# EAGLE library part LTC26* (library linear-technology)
Dual 16-/14-/12-Bit Rail-to-Rail DACs Source: www.linear.com

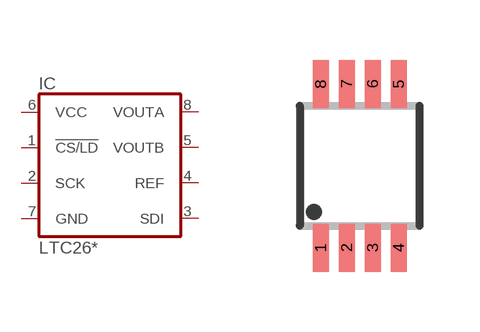
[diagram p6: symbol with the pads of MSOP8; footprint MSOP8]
Designator prefix IC

## LTC2602CMS8 (MPN: LTC2602CMS8; OC_FARNELL: 1330944; OC_NEWARK: 56M5818), LTC2602IMS8 (MPN: LTC2602IMS8; OC_FARNELL: 1663694; OC_NEWARK: 56M5822), LTC2612CMS8 (MPN: LTC2612CMS8; OC_FARNELL: 1330947; OC_NEWARK: 56M5926), LTC2612IMS8 (MPN: LTC2612IMS8; OC_FARNELL: unknown; OC_NEWARK: 56M5930), LTC2622CMS8 (MPN: LTC2622CMS8; OC_FARNELL: 1330954; OC_NEWARK: 56M6034), LTC2622IMS8 (MPN: LTC2622IMS8; OC_FARNELL: unknown; OC_NEWARK: 56M6038)  [MSOP8]
1  !CS/LD  in
2  SCK  in
3  SDI  in
4  REF  in
5  VOUTB  out
6  VCC  pwr
7  GND  pwr
8  VOUTA  out

## Footprint MSOP8 (pad centres in mm)
MSOP8
smd 0.4 x 1.2: 1 -0.975,-2.05; 2 -0.325,-2.05; 3 0.325,-2.05; 4 0.975,-2.05; 5 0.975,2.05; 6 0.325,2.05; 7 -0.325,2.05; 8 -0.975,2.05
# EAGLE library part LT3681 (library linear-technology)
36V, 2A, 2.8MHz Step-Down Switching Regulator with Integrated Power Schottky Diode Source: http://www.linear.com/pc/downloadDocument.do?navId=H0,C1,C1003,C1042,C1032,C1064,P38040,D25144

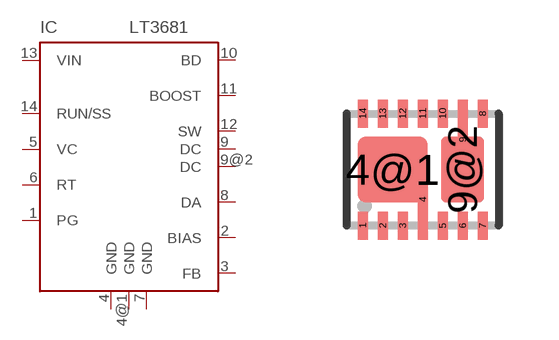
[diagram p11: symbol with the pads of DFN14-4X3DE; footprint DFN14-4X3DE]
Designator prefix IC

## LT3681 (MPN: LT3681EDE#PBF; OC_FARNELL: 1627603; OC_NEWARK: 57M8550)  [DFN14-4X3DE]
1  PG  oc
2  BIAS  in
3  FB  in
4  GND  in
4@1  GND  in
5  VC  out
6  RT  in
7  GND  in
8  DA  pas
9  DC  pas
9@2  DC  pas
10  BD  in
11  BOOST  out
12  SW  out
13  VIN  in
14  RUN/SS  in

## Footprint DFN14-4X3DE (pad centres in mm)
14-LEAD (4mm x 2mm) PALSTIC DFN DE14MA PACKAGE Source: http://www.linear.com/pc/downloadDocument.do?navId=H0,C1,C1003,C1042,C1032,C1064,P38040,D25144
smd 0.25 x 0.7: 1 -1.5,-1.4; 2 -1,-1.4; 3 -0.5,-1.4; 5 0.5,-1.4; 6 1,-1.4; 7 1.5,-1.4; 8 1.5,1.4; 10 0.5,1.4; 11 0,1.4; 12 -0.5,1.4; 13 -1,1.4; 14 -1.5,1.4
smd 0.25 x 2: 4 0,-0.75; 9 1,0.75
smd 1.75 x 1.65: 4@1 -0.75,0
smd 1.07 x 1.65: 9@2 1,0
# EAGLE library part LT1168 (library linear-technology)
Low Power, Single Resistor Gain Programmable, Precision Instrumentation Amplifier SourcE: LT1168.pdf

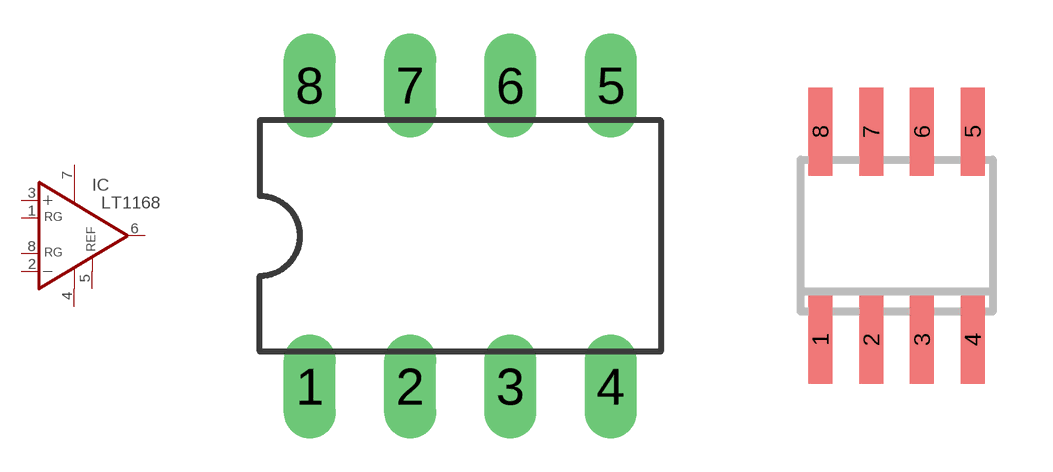
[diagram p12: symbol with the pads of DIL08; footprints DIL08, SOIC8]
Designator prefix IC

## LT1168ACN8 (OC_FARNELL: unknown; OC_NEWARK: unknown), LT1168AIN8 (OC_FARNELL: unknown; OC_NEWARK: unknown), LT1168CN8 (MPN: LT1168CN8#PBF; OC_FARNELL: 1330587; OC_NEWARK: 57M2327), LT1168IN8 (MPN: LT1168IN8; OC_FARNELL: unknown; OC_NEWARK: 57M2332)  [DIL08]
1  RG  in
2  -IN  in
3  +IN  in
4  V-  pwr
5  REF  in
6  OUT  out
7  V+  pwr
8  RG  in

## LT1168ACS8 (MPN: LT1168ACS8; OC_FARNELL: unknown; OC_NEWARK: 57M2316), LT1168AIS8 (MPN: LT1168AIS8; OC_FARNELL: unknown; OC_NEWARK: 57M2322), LT1168CS8 (MPN: LT1168CS8; OC_FARNELL: unknown; OC_NEWARK: 57M2328), LT1168IS8 (MPN: LT1168IS8; OC_FARNELL: unknown; OC_NEWARK: 57M2334)  [SOIC8]
Pads as for DIL08

## Footprint DIL08 (pad centres in mm)
Dual In Line Package
drill 0.813 long: 1 -3.81,-3.81; 2 -1.27,-3.81; 3 1.27,-3.81; 4 3.81,-3.81; 5 3.81,3.81; 6 1.27,3.81; 7 -1.27,3.81; 8 -3.81,3.81

## Footprint SOIC8 (pad centres in mm)
Small Outline IC
smd 0.6 x 2.2: 1 -1.905,-2.6; 2 -0.635,-2.6; 3 0.635,-2.6; 4 1.905,-2.6; 5 1.905,2.6; 6 0.635,2.6; 7 -0.635,2.6; 8 -1.905,2.6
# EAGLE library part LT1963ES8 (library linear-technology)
1.5A, Low Noise, Fast Transient Response LDO Regulator Source: http://www.linear.com/pc/downloadDocument.do?navId=H0,C3,P2222,D3148

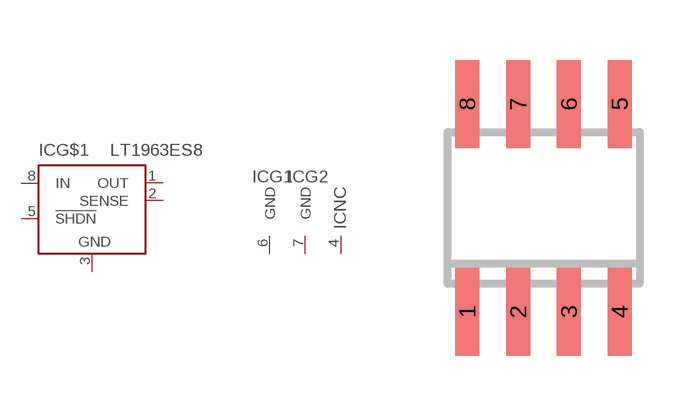
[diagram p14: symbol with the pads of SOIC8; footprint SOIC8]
Designator prefix IC; gates G$1=LT1129 G1=GND G2=GND NC=NC

## LT1963ES8 (MPN: LT1963ES8; OC_FARNELL: unknown; OC_NEWARK: 57M7550), LT1963ES8-1.5 (MPN: LT1963ES8-1.5; OC_FARNELL: unknown; OC_NEWARK: 57M7551), LT1963ES8-1.8 (MPN: LT1963ES8-1.8; OC_FARNELL: unknown; OC_NEWARK: 57M7555), LT1963ES8-2.5 (MPN: LT1963ES8-2.5; OC_FARNELL: unknown; OC_NEWARK: 57M7559), LT1963ES8-3.3 (MPN: LT1963ES8-3.3; OC_FARNELL: unknown; OC_NEWARK: 57M7563)  [SOIC8]
1  G$1:OUT  out
2  G$1:SENSE  in
3  G$1:GND  pwr
4  NC:NC  nc
5  G$1:!SHDN  in
6  G1:GND  pwr
7  G2:GND  pwr
8  G$1:IN  in

## Footprint SOIC8 (pad centres in mm)
Small Outline IC
smd 0.6 x 2.2: 1 -1.905,-2.6; 2 -0.635,-2.6; 3 0.635,-2.6; 4 1.905,-2.6; 5 1.905,2.6; 6 0.635,2.6; 7 -0.635,2.6; 8 -1.905,2.6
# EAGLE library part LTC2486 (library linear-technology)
16-Bit 2-/4-Channel Delta Sigma ADC with PGA and Easy Drive Input Current Cancellation Source: http://www.linear.com/pc/downloadDocument.do?navId=H0,C1,C1155,C1001,C1152,P36532,D19318

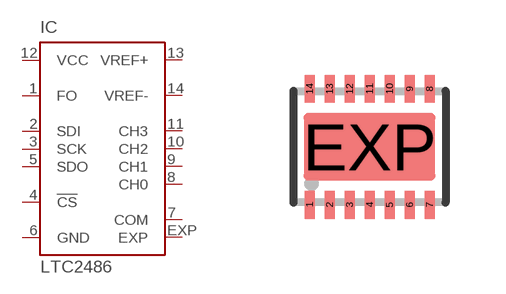
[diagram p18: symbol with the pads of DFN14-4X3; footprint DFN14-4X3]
Designator prefix IC

## LTC2486C (OC_FARNELL: unknown; OC_NEWARK: unknown), LTC2486I (OC_FARNELL: unknown; OC_NEWARK: unknown)  [DFN14-4X3]
1  FO  in
2  SDI  in
3  SCK  in
4  !CS  in
5  SDO  out
6  GND  pwr
7  COM  pwr
8  CH0  in
9  CH1  in
10  CH2  in
11  CH3  in
12  VCC  pwr
13  VREF+  in
14  VREF-  in
EXP  EXP  in

## Footprint DFN14-4X3 (pad centres in mm)
14-Lead Plastic DFN (4mm × 3mm) (Reference LTC DWG # 05-08-1708 Rev B) Source: http://www.linear.com/pc/downloadDocument.do?navId=H0,C1,C1155,C1001,C1152,P36532,D19318
smd 0.25 x 0.7: 1 -1.5,-1.45; 2 -1,-1.45; 3 -0.5,-1.45; 4 0,-1.45; 5 0.5,-1.45; 6 1,-1.45; 7 1.5,-1.45; 8 1.5,1.45; 9 1,1.45; 10 0.5,1.45; 11 0,1.45; 12 -0.5,1.45; 13 -1,1.45; 14 -1.5,1.45
smd 3.3 x 1.7: EXP 0,0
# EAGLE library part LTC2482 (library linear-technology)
16-Bit Delta Sigma ADC with Easy Drive Input Current Cancellation Source: http://www.linear.com/pc/downloadDocument.do?navId=H0,C1,C1155,C1001,C1152,P11253,D7998

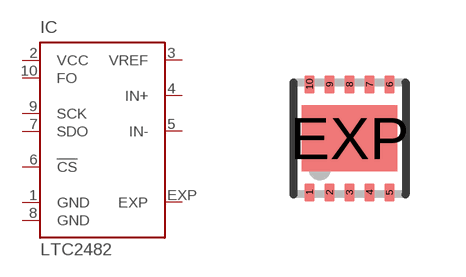
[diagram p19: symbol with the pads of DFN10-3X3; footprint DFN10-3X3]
Designator prefix IC

## LTC2482 (OC_FARNELL: 1330940; OC_NEWARK: unknown)  [DFN10-3X3]
1  GND  pwr
2  VCC  pwr
3  VREF  in
4  IN+  in
5  IN-  in
6  !CS  in
7  SDO  out
8  GND  pwr
9  SCK  in
10  FO  in
EXP  EXP  in

## Footprint DFN10-3X3 (pad centres in mm)
DD Package 10-Lead Plastic DFN (3mm × 3mm) (Reference LTC DWG # 05-08-1669) Source: http://www.linear.com .. 4062fa.pdf
smd 0.25 x 0.45: 1 -1,-1.35; 2 -0.5,-1.35; 3 0,-1.35; 4 0.5,-1.35; 5 1,-1.35; 6 1,1.35; 7 0.5,1.35; 8 0,1.35; 9 -0.5,1.35; 10 -1,1.35
smd 2.38 x 1.65: EXP 0,0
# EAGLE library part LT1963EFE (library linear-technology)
1.5A, Low Noise, Fast Transient Response LDO Regulator Source: http://cds.linear.com/docs/Datasheet/1963fc.pdf

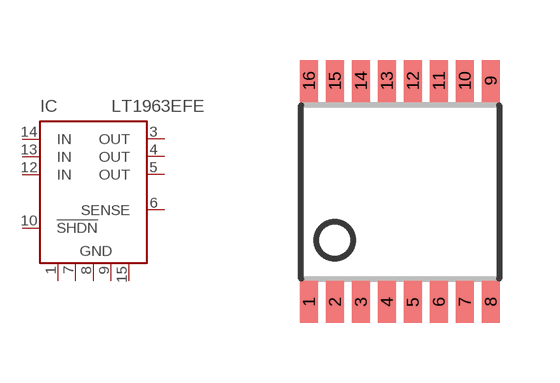
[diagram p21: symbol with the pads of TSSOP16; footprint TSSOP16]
Designator prefix IC

## LT1963EFE (MPN: LT1963EFE; OC_FARNELL: unknown; OC_NEWARK: 57M7494), LT1963EFE-1.5 (MPN: LT1963EFE-1.5; OC_FARNELL: unknown; OC_NEWARK: 57M7495), LT1963EFE-1.8 (MPN: LT1963EFE-1.8; OC_FARNELL: unknown; OC_NEWARK: 57M7499), LT1963EFE-2.5 (MPN: LT1963EFE-2.5; OC_FARNELL: unknown; OC_NEWARK: 57M7503), LT1963EFE-3.3 (MPN: LT1963EFE-3.3; OC_FARNELL: unknown; OC_NEWARK: 57M7507)  [TSSOP16]
1  GND  pwr
3  OUT  out
4  OUT  out
5  OUT  out
6  SENSE  in
7  GND  pwr
8  GND  pwr
9  GND  pwr
10  !SHDN  in
12  IN  in
13  IN  in
14  IN  in
15  GND  pwr

## Footprint TSSOP16 (pad centres in mm)
16-Lead Plastic TSSOP (4.4mm) http://cds.linear.com/docs/Datasheet/1963fc.pdf
smd 0.45 x 1.05: 1 -2.275,-2.768; 2 -1.625,-2.768; 3 -0.975,-2.768; 4 -0.325,-2.768; 5 0.325,-2.768; 6 0.975,-2.768; 7 1.625,-2.768; 8 2.275,-2.768; 9 2.275,2.768; 10 1.625,2.768; 11 0.975,2.768; 12 0.325,2.768; 13 -0.325,2.768; 14 -0.975,2.768; 15 -1.625,2.768; 16 -2.275,2.768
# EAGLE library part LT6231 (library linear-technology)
215MHz, Rail-to-Rail Output, 1.1nV/Hz, 3.5mA Op Amp Source: http://cds.linear.com/docs/Datasheet/623012fb.pdf

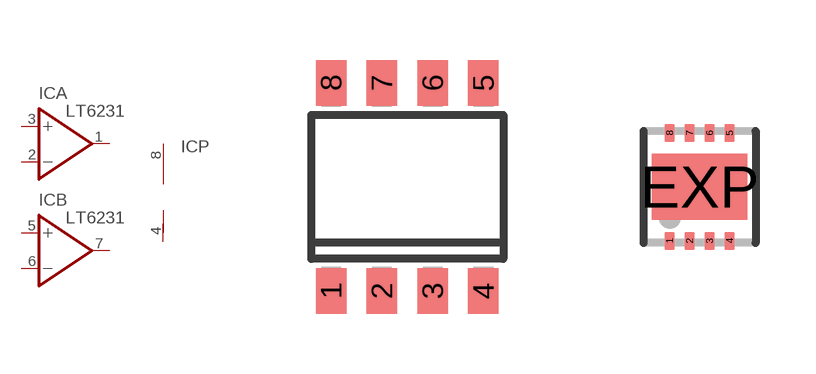
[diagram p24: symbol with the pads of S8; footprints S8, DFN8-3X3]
Designator prefix IC; gates A=OPAMP B=OPAMP P=V+-

## LT6231CS8 (MPN: LT6231CS8; OC_FARNELL: 1330763; OC_NEWARK: 57M9348), LT6231IS8 (MPN: LT6231IS8; OC_FARNELL: unknown; OC_NEWARK: 57M9356)  [S8]
1  A:OUT  out
2  A:-IN  in
3  A:+IN  in
4  P:V-  pwr
5  B:+IN  in
6  B:-IN  in
7  B:OUT  out
8  P:V+  pwr

## LT6231CDD (MPN: LT6231CDD; OC_FARNELL: unknown; OC_NEWARK: 57M9344), LT6231IDD (MPN: LT6231IDD; OC_FARNELL: unknown; OC_NEWARK: 57M9352)  [DFN8-3X3]
Pads as for S8

## Footprint S8 (pad centres in mm)
8-Lead Plastic Small Outline Narrow .150 Inch Source: http://cds.linear.com/docs/Datasheet/623012fb.pdf
smd 0.762 x 1.143: 1 -1.905,-2.6; 2 -0.635,-2.6; 3 0.635,-2.6; 4 1.905,-2.6; 5 1.905,2.6; 6 0.635,2.6; 7 -0.635,2.6; 8 -1.905,2.6

## Footprint DFN8-3X3 (pad centres in mm)
DD Package 8-Lead Plastic DFN (3mm × 3mm) Source: http://cds.linear.com/docs/Datasheet/623012fb.pdf
smd 0.25 x 0.45: 1 -0.75,-1.35; 2 -0.25,-1.35; 3 0.25,-1.35; 4 0.75,-1.35; 5 0.75,1.35; 6 0.25,1.35; 7 -0.25,1.35; 8 -0.75,1.35
smd 2.38 x 1.65: EXP 0,0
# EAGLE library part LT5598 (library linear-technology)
5MHz to 1600MHz High Linearity Direct Quadrature Modulator Source: http://cds.linear.com/docs/Datasheet/5598f.pdf

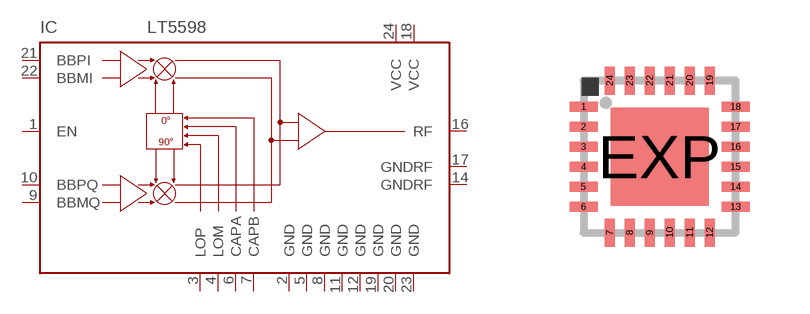
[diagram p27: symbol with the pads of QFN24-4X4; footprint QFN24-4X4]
Designator prefix IC

## LT5598IUF (OC_FARNELL: unknown; OC_NEWARK: unknown)  [QFN24-4X4]
1  EN  in
2  GND  pwr
3  LOP  in
4  LOM  in
5  GND  pwr
6  CAPA  in
7  CAPB  in
8  GND  pwr
9  BBMQ  in
10  BBPQ  in
11  GND  pwr
12  GND  pwr
14  GNDRF  pwr
16  RF  out
17  GNDRF  pwr
18  VCC  pwr
19  GND  pwr
20  GND  pwr
21  BBPI  in
22  BBMI  in
23  GND  pwr
24  VCC  pwr

## Footprint QFN24-4X4 (pad centres in mm)
UF Package 24-Lead (4mm × 4mm) Plastic QFN Source: http://cds.linear.com/docs/Datasheet/5598f.pdf
smd 0.7 x 0.25: 1 -1.9,1.25; 2 -1.9,0.75; 3 -1.9,0.25; 4 -1.9,-0.25; 5 -1.9,-0.75; 6 -1.9,-1.25; 13 1.9,-1.25; 14 1.9,-0.75; 15 1.9,-0.25; 16 1.9,0.25; 17 1.9,0.75; 18 1.9,1.25
smd 0.25 x 0.7: 7 -1.25,-1.9; 8 -0.75,-1.9; 9 -0.25,-1.9; 10 0.25,-1.9; 11 0.75,-1.9; 12 1.25,-1.9; 19 1.25,1.9; 20 0.75,1.9; 21 0.25,1.9; 22 -0.25,1.9; 23 -0.75,1.9; 24 -1.25,1.9
smd 2.45 x 2.45: EXP 0,0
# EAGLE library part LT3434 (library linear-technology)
High Voltage 3A, 200kHz Step-Down Switching Regulator with 100µA Quiescent Current Spurce: www.linear.com .. 3434fb.pdf

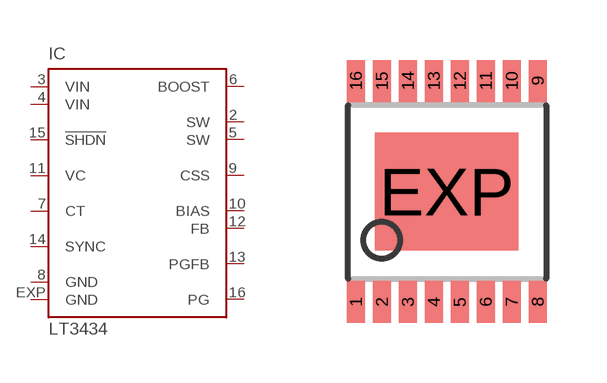
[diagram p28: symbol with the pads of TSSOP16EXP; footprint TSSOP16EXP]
Designator prefix IC

## LT3434 (MPN: LT3434EFE#PBF; OC_FARNELL: 1501035; OC_NEWARK: 57M8118)  [TSSOP16EXP]
2  SW  out
3  VIN  in
4  VIN  in
5  SW  pas
6  BOOST  in
7  CT  pas
8  GND  pwr
9  CSS  in
10  BIAS  in
11  VC  pas
12  FB  in
13  PGFB  in
14  SYNC  in
15  !SHDN  in
16  PG  oc
EXP  GND  pwr

## Footprint TSSOP16EXP (pad centres in mm)
16-Lead Plastic TSSOP (4.4mm) EXPOSED PAD http://cds.linear.com/docs/Datasheet/1963fc.pdf
smd 0.45 x 1.05: 1 -2.275,-2.768; 2 -1.625,-2.768; 3 -0.975,-2.768; 4 -0.325,-2.768; 5 0.325,-2.768; 6 0.975,-2.768; 7 1.625,-2.768; 8 2.275,-2.768; 9 2.275,2.768; 10 1.625,2.768; 11 0.975,2.768; 12 0.325,2.768; 13 -0.325,2.768; 14 -0.975,2.768; 15 -1.625,2.768; 16 -2.275,2.768
smd 3.58 x 2.94: EXP 0,0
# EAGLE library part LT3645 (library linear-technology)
36V 500mA Step-Down Regulator and 200mA LDO Source: http://cds.linear.com/docs/en/datasheet/3645f.pdf

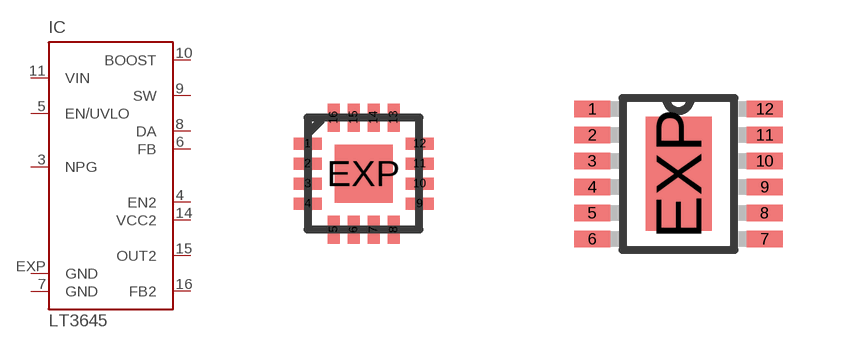
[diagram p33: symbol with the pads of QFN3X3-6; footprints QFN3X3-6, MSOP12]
Designator prefix IC

## LT3645EUD, LT3645IUD  [QFN3X3-6]
3  NPG  out
4  EN2  in
5  EN/UVLO  in
6  FB  in
7  GND  pwr
8  DA  in
9  SW  oc
10  BOOST  in
11  VIN  in
14  VCC2  in
15  OUT2  out
16  FB2  in
EXP  GND  pwr

## LT3645MSE  [MSOP12]
1  EN/UVLO  in
2  FB  in
3  GND  pwr
4  DA  in
5  BOOST  in
6  SW  oc
7  VIN  in
8  VCC2  in
9  OUT2  out
10  FB2  in
11  EN2  in
12  NPG  out
EXP  GND  pwr

## Footprint QFN3X3-6 (pad centres in mm)
16-Lead Plastic QFN (3mm × 3mm) Auto generated by make-symbol-device-package-bsdl.ulp Rev. 44 Source: http://cds.linear.com/docs/en/datasheet/3645f.pdf
smd 0.7 x 0.3: 1 -1.4,0.75; 2 -1.4,0.25; 3 -1.4,-0.25; 4 -1.4,-0.75; 9 1.4,-0.75; 10 1.4,-0.25; 11 1.4,0.25; 12 1.4,0.75
smd 0.3 x 0.7: 5 -0.75,-1.4; 6 -0.25,-1.4; 7 0.25,-1.4; 8 0.75,-1.4; 13 0.75,1.4; 14 0.25,1.4; 15 -0.25,1.4; 16 -0.75,1.4
smd 1.45 x 1.45: EXP 0,0

## Footprint MSOP12 (pad centres in mm)
MSE Package 12-Lead Plastic MSOP Exposed Die Pad (Reference LTC DWG # 05-08-1666 Rev D) Source: http://cds.linear.com/docs/en/datasheet/3645f.pdf Auto generated by make-symbol-device-package-bsdl.ulp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
smd 0.9 x 0.42: 1 -2.163,1.625; 2 -2.163,0.975; 3 -2.163,0.325; 4 -2.163,-0.325; 5 -2.163,-0.975; 6 -2.163,-1.625; 7 2.15,-1.625; 8 2.15,-0.975; 9 2.15,-0.325; 10 2.15,0.325; 11 2.15,0.975; 12 2.15,1.625
smd 1.65 x 2.85: EXP 0,0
